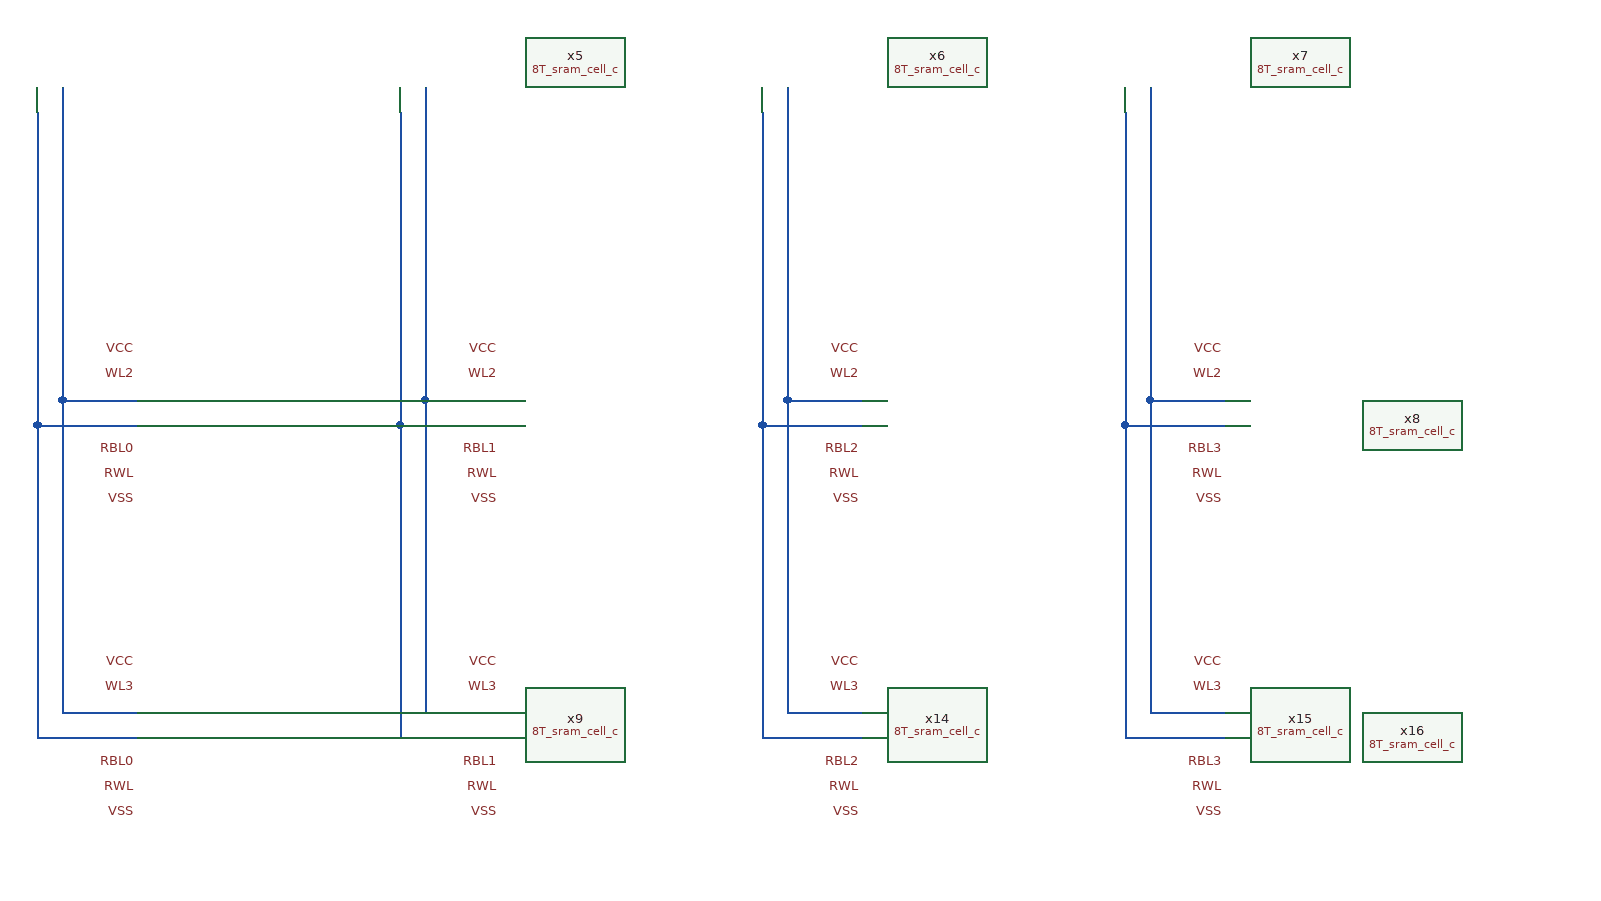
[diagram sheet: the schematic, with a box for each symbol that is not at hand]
v {xschem version=3.4.8RC file_version=1.3}
G {}
K {}
V {}
S {}
F {}
E {}
N 860 -1810 860 -1560 {lab=BL0}
N 860 -1560 940 -1560 {lab=BL0}
N 880 -1830 880 -1580 {lab=BLB0}
N 880 -1580 940 -1580 {lab=BLB0}
N 1150 -1810 1150 -1560 {lab=BL1}
N 1150 -1560 1230 -1560 {lab=BL1}
N 1170 -1830 1170 -1580 {lab=BLB1}
N 1170 -1580 1230 -1580 {lab=BLB1}
N 1440 -1810 1440 -1560 {lab=BL2}
N 1440 -1560 1520 -1560 {lab=BL2}
N 1460 -1830 1460 -1580 {lab=BLB2}
N 1460 -1580 1520 -1580 {lab=BLB2}
N 1730 -1810 1730 -1560 {lab=BL3}
N 1730 -1560 1810 -1560 {lab=BL3}
N 1750 -1830 1750 -1580 {lab=BLB3}
N 1750 -1580 1810 -1580 {lab=BLB3}
N 860 -1560 860 -1310 {lab=BL0}
N 860 -1310 940 -1310 {lab=BL0}
N 880 -1580 880 -1330 {lab=BLB0}
N 880 -1330 940 -1330 {lab=BLB0}
N 1150 -1560 1150 -1310 {lab=BL1}
N 1150 -1310 1230 -1310 {lab=BL1}
N 1170 -1580 1170 -1330 {lab=BLB1}
N 1170 -1330 1230 -1330 {lab=BLB1}
N 1440 -1560 1440 -1310 {lab=BL2}
N 1440 -1310 1520 -1310 {lab=BL2}
N 1460 -1580 1460 -1330 {lab=BLB2}
N 1460 -1330 1520 -1330 {lab=BLB2}
N 1730 -1560 1730 -1310 {lab=BL3}
N 1730 -1310 1810 -1310 {lab=BL3}
N 1750 -1580 1750 -1330 {lab=BLB3}
N 1750 -1330 1810 -1330 {lab=BLB3}
C {lab_pin.sym} 940 -1500 0 0 {name=p11 sig_type=std_logic lab=VSS}
C {lab_pin.sym} 940 -1520 0 0 {name=p14 sig_type=std_logic lab=RWL}
C {lab_pin.sym} 1230 -1500 0 0 {name=p16 sig_type=std_logic lab=VSS}
C {8T_sram_cell_c.sym} 1090 -1560 0 1 {name=x5}
C {lab_pin.sym} 1230 -1520 0 0 {name=p21 sig_type=std_logic lab=RWL}
C {lab_pin.sym} 1520 -1500 0 0 {name=p24 sig_type=std_logic lab=VSS}
C {8T_sram_cell_c.sym} 1380 -1560 0 1 {name=x6}
C {lab_pin.sym} 1520 -1520 0 0 {name=p25 sig_type=std_logic lab=RWL}
C {lab_pin.sym} 1810 -1500 0 0 {name=p27 sig_type=std_logic lab=VSS}
C {8T_sram_cell_c.sym} 1670 -1560 0 1 {name=x7}
C {lab_pin.sym} 1810 -1520 0 0 {name=p30 sig_type=std_logic lab=RWL}
C {8T_sram_cell_c.sym} 1960 -1560 0 1 {name=x8}
C {lab_pin.sym} 940 -1620 0 0 {name=p34 sig_type=std_logic lab=VCC}
C {lab_pin.sym} 1230 -1620 0 0 {name=p35 sig_type=std_logic lab=VCC}
C {lab_pin.sym} 1520 -1620 0 0 {name=p38 sig_type=std_logic lab=VCC}
C {lab_pin.sym} 1810 -1620 0 0 {name=p42 sig_type=std_logic lab=VCC}
C {lab_pin.sym} 940 -1600 0 0 {name=p44 sig_type=std_logic lab=WL2}
C {lab_pin.sym} 1230 -1600 0 0 {name=p45 sig_type=std_logic lab=WL2}
C {lab_pin.sym} 1520 -1600 0 0 {name=p47 sig_type=std_logic lab=WL2}
C {lab_pin.sym} 1810 -1600 0 0 {name=p48 sig_type=std_logic lab=WL2}
C {lab_pin.sym} 1810 -1540 0 0 {name=p49 sig_type=std_logic lab=RBL3}
C {lab_pin.sym} 1520 -1540 0 0 {name=p53 sig_type=std_logic lab=RBL2}
C {lab_pin.sym} 1230 -1540 0 0 {name=p54 sig_type=std_logic lab=RBL1}
C {lab_pin.sym} 940 -1540 0 0 {name=p55 sig_type=std_logic lab=RBL0}
C {lab_pin.sym} 940 -1250 0 0 {name=p56 sig_type=std_logic lab=VSS}
C {lab_pin.sym} 940 -1270 0 0 {name=p57 sig_type=std_logic lab=RWL}
C {lab_pin.sym} 1230 -1250 0 0 {name=p58 sig_type=std_logic lab=VSS}
C {8T_sram_cell_c.sym} 1090 -1310 0 1 {name=x9}
C {lab_pin.sym} 1230 -1270 0 0 {name=p61 sig_type=std_logic lab=RWL}
C {lab_pin.sym} 1520 -1250 0 0 {name=p66 sig_type=std_logic lab=VSS}
C {8T_sram_cell_c.sym} 1380 -1310 0 1 {name=x14}
C {lab_pin.sym} 1520 -1270 0 0 {name=p67 sig_type=std_logic lab=RWL}
C {lab_pin.sym} 1810 -1250 0 0 {name=p68 sig_type=std_logic lab=VSS}
C {8T_sram_cell_c.sym} 1670 -1310 0 1 {name=x15}
C {lab_pin.sym} 1810 -1270 0 0 {name=p94 sig_type=std_logic lab=RWL}
C {8T_sram_cell_c.sym} 1960 -1310 0 1 {name=x16}
C {lab_pin.sym} 940 -1370 0 0 {name=p97 sig_type=std_logic lab=VCC}
C {lab_pin.sym} 1230 -1370 0 0 {name=p98 sig_type=std_logic lab=VCC}
C {lab_pin.sym} 1520 -1370 0 0 {name=p100 sig_type=std_logic lab=VCC}
C {lab_pin.sym} 1810 -1370 0 0 {name=p101 sig_type=std_logic lab=VCC}
C {lab_pin.sym} 940 -1350 0 0 {name=p102 sig_type=std_logic lab=WL3}
C {lab_pin.sym} 1230 -1350 0 0 {name=p103 sig_type=std_logic lab=WL3}
C {lab_pin.sym} 1520 -1350 0 0 {name=p104 sig_type=std_logic lab=WL3}
C {lab_pin.sym} 1810 -1350 0 0 {name=p106 sig_type=std_logic lab=WL3}
C {lab_pin.sym} 1810 -1290 0 0 {name=p109 sig_type=std_logic lab=RBL3}
C {lab_pin.sym} 1520 -1290 0 0 {name=p110 sig_type=std_logic lab=RBL2}
C {lab_pin.sym} 1230 -1290 0 0 {name=p111 sig_type=std_logic lab=RBL1}
C {lab_pin.sym} 940 -1290 0 0 {name=p115 sig_type=std_logic lab=RBL0}
